# Generated by innovus_enablement/scripts/gen_fakeram.py: abstract 256x32 SRAM.
# Geometry is an assumption (see script header), not PDK data.
VERSION 5.8 ;
BUSBITCHARS "[]" ;
DIVIDERCHAR "/" ;

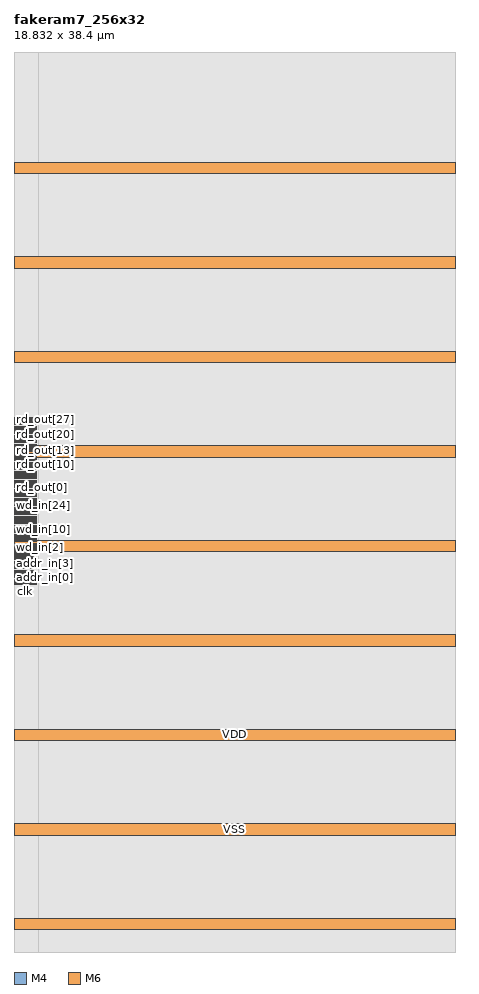
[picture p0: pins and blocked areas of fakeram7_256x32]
MACRO fakeram7_256x32
  CLASS BLOCK ;
  FOREIGN fakeram7_256x32 0 0 ;
  ORIGIN 0 0 ;
  SIZE 18.8320 BY 38.4000 ;
  SYMMETRY X Y R90 ;
  PIN clk
    DIRECTION INPUT ;
    USE CLOCK ;
    PORT
      LAYER M4 ;
        RECT 0 15.6720 0.9600 15.7200 ;
    END
  END clk
  PIN ce_in
    DIRECTION INPUT ;
    USE SIGNAL ;
    PORT
      LAYER M4 ;
        RECT 0 15.7680 0.9600 15.8160 ;
    END
  END ce_in
  PIN we_in
    DIRECTION INPUT ;
    USE SIGNAL ;
    PORT
      LAYER M4 ;
        RECT 0 15.8640 0.9600 15.9120 ;
    END
  END we_in
  PIN addr_in[0]
    DIRECTION INPUT ;
    USE SIGNAL ;
    PORT
      LAYER M4 ;
        RECT 0 15.9600 0.9600 16.0080 ;
    END
  END addr_in[0]
  PIN addr_in[1]
    DIRECTION INPUT ;
    USE SIGNAL ;
    PORT
      LAYER M4 ;
        RECT 0 16.0560 0.9600 16.1040 ;
    END
  END addr_in[1]
  PIN addr_in[2]
    DIRECTION INPUT ;
    USE SIGNAL ;
    PORT
      LAYER M4 ;
        RECT 0 16.1520 0.9600 16.2000 ;
    END
  END addr_in[2]
  PIN addr_in[3]
    DIRECTION INPUT ;
    USE SIGNAL ;
    PORT
      LAYER M4 ;
        RECT 0 16.2480 0.9600 16.2960 ;
    END
  END addr_in[3]
  PIN addr_in[4]
    DIRECTION INPUT ;
    USE SIGNAL ;
    PORT
      LAYER M4 ;
        RECT 0 16.3440 0.9600 16.3920 ;
    END
  END addr_in[4]
  PIN addr_in[5]
    DIRECTION INPUT ;
    USE SIGNAL ;
    PORT
      LAYER M4 ;
        RECT 0 16.4400 0.9600 16.4880 ;
    END
  END addr_in[5]
  PIN addr_in[6]
    DIRECTION INPUT ;
    USE SIGNAL ;
    PORT
      LAYER M4 ;
        RECT 0 16.5360 0.9600 16.5840 ;
    END
  END addr_in[6]
  PIN addr_in[7]
    DIRECTION INPUT ;
    USE SIGNAL ;
    PORT
      LAYER M4 ;
        RECT 0 16.6320 0.9600 16.6800 ;
    END
  END addr_in[7]
  PIN wd_in[0]
    DIRECTION INPUT ;
    USE SIGNAL ;
    PORT
      LAYER M4 ;
        RECT 0 16.7280 0.9600 16.7760 ;
    END
  END wd_in[0]
  PIN wd_in[1]
    DIRECTION INPUT ;
    USE SIGNAL ;
    PORT
      LAYER M4 ;
        RECT 0 16.8240 0.9600 16.8720 ;
    END
  END wd_in[1]
  PIN wd_in[2]
    DIRECTION INPUT ;
    USE SIGNAL ;
    PORT
      LAYER M4 ;
        RECT 0 16.9200 0.9600 16.9680 ;
    END
  END wd_in[2]
  PIN wd_in[3]
    DIRECTION INPUT ;
    USE SIGNAL ;
    PORT
      LAYER M4 ;
        RECT 0 17.0160 0.9600 17.0640 ;
    END
  END wd_in[3]
  PIN wd_in[4]
    DIRECTION INPUT ;
    USE SIGNAL ;
    PORT
      LAYER M4 ;
        RECT 0 17.1120 0.9600 17.1600 ;
    END
  END wd_in[4]
  PIN wd_in[5]
    DIRECTION INPUT ;
    USE SIGNAL ;
    PORT
      LAYER M4 ;
        RECT 0 17.2080 0.9600 17.2560 ;
    END
  END wd_in[5]
  PIN wd_in[6]
    DIRECTION INPUT ;
    USE SIGNAL ;
    PORT
      LAYER M4 ;
        RECT 0 17.3040 0.9600 17.3520 ;
    END
  END wd_in[6]
  PIN wd_in[7]
    DIRECTION INPUT ;
    USE SIGNAL ;
    PORT
      LAYER M4 ;
        RECT 0 17.4000 0.9600 17.4480 ;
    END
  END wd_in[7]
  PIN wd_in[8]
    DIRECTION INPUT ;
    USE SIGNAL ;
    PORT
      LAYER M4 ;
        RECT 0 17.4960 0.9600 17.5440 ;
    END
  END wd_in[8]
  PIN wd_in[9]
    DIRECTION INPUT ;
    USE SIGNAL ;
    PORT
      LAYER M4 ;
        RECT 0 17.5920 0.9600 17.6400 ;
    END
  END wd_in[9]
  PIN wd_in[10]
    DIRECTION INPUT ;
    USE SIGNAL ;
    PORT
      LAYER M4 ;
        RECT 0 17.6880 0.9600 17.7360 ;
    END
  END wd_in[10]
  PIN wd_in[11]
    DIRECTION INPUT ;
    USE SIGNAL ;
    PORT
      LAYER M4 ;
        RECT 0 17.7840 0.9600 17.8320 ;
    END
  END wd_in[11]
  PIN wd_in[12]
    DIRECTION INPUT ;
    USE SIGNAL ;
    PORT
      LAYER M4 ;
        RECT 0 17.8800 0.9600 17.9280 ;
    END
  END wd_in[12]
  PIN wd_in[13]
    DIRECTION INPUT ;
    USE SIGNAL ;
    PORT
      LAYER M4 ;
        RECT 0 17.9760 0.9600 18.0240 ;
    END
  END wd_in[13]
  PIN wd_in[14]
    DIRECTION INPUT ;
    USE SIGNAL ;
    PORT
      LAYER M4 ;
        RECT 0 18.0720 0.9600 18.1200 ;
    END
  END wd_in[14]
  PIN wd_in[15]
    DIRECTION INPUT ;
    USE SIGNAL ;
    PORT
      LAYER M4 ;
        RECT 0 18.1680 0.9600 18.2160 ;
    END
  END wd_in[15]
  PIN wd_in[16]
    DIRECTION INPUT ;
    USE SIGNAL ;
    PORT
      LAYER M4 ;
        RECT 0 18.2640 0.9600 18.3120 ;
    END
  END wd_in[16]
  PIN wd_in[17]
    DIRECTION INPUT ;
    USE SIGNAL ;
    PORT
      LAYER M4 ;
        RECT 0 18.3600 0.9600 18.4080 ;
    END
  END wd_in[17]
  PIN wd_in[18]
    DIRECTION INPUT ;
    USE SIGNAL ;
    PORT
      LAYER M4 ;
        RECT 0 18.4560 0.9600 18.5040 ;
    END
  END wd_in[18]
  PIN wd_in[19]
    DIRECTION INPUT ;
    USE SIGNAL ;
    PORT
      LAYER M4 ;
        RECT 0 18.5520 0.9600 18.6000 ;
    END
  END wd_in[19]
  PIN wd_in[20]
    DIRECTION INPUT ;
    USE SIGNAL ;
    PORT
      LAYER M4 ;
        RECT 0 18.6480 0.9600 18.6960 ;
    END
  END wd_in[20]
  PIN wd_in[21]
    DIRECTION INPUT ;
    USE SIGNAL ;
    PORT
      LAYER M4 ;
        RECT 0 18.7440 0.9600 18.7920 ;
    END
  END wd_in[21]
  PIN wd_in[22]
    DIRECTION INPUT ;
    USE SIGNAL ;
    PORT
      LAYER M4 ;
        RECT 0 18.8400 0.9600 18.8880 ;
    END
  END wd_in[22]
  PIN wd_in[23]
    DIRECTION INPUT ;
    USE SIGNAL ;
    PORT
      LAYER M4 ;
        RECT 0 18.9360 0.9600 18.9840 ;
    END
  END wd_in[23]
  PIN wd_in[24]
    DIRECTION INPUT ;
    USE SIGNAL ;
    PORT
      LAYER M4 ;
        RECT 0 19.0320 0.9600 19.0800 ;
    END
  END wd_in[24]
  PIN wd_in[25]
    DIRECTION INPUT ;
    USE SIGNAL ;
    PORT
      LAYER M4 ;
        RECT 0 19.1280 0.9600 19.1760 ;
    END
  END wd_in[25]
  PIN wd_in[26]
    DIRECTION INPUT ;
    USE SIGNAL ;
    PORT
      LAYER M4 ;
        RECT 0 19.2240 0.9600 19.2720 ;
    END
  END wd_in[26]
  PIN wd_in[27]
    DIRECTION INPUT ;
    USE SIGNAL ;
    PORT
      LAYER M4 ;
        RECT 0 19.3200 0.9600 19.3680 ;
    END
  END wd_in[27]
  PIN wd_in[28]
    DIRECTION INPUT ;
    USE SIGNAL ;
    PORT
      LAYER M4 ;
        RECT 0 19.4160 0.9600 19.4640 ;
    END
  END wd_in[28]
  PIN wd_in[29]
    DIRECTION INPUT ;
    USE SIGNAL ;
    PORT
      LAYER M4 ;
        RECT 0 19.5120 0.9600 19.5600 ;
    END
  END wd_in[29]
  PIN wd_in[30]
    DIRECTION INPUT ;
    USE SIGNAL ;
    PORT
      LAYER M4 ;
        RECT 0 19.6080 0.9600 19.6560 ;
    END
  END wd_in[30]
  PIN wd_in[31]
    DIRECTION INPUT ;
    USE SIGNAL ;
    PORT
      LAYER M4 ;
        RECT 0 19.7040 0.9600 19.7520 ;
    END
  END wd_in[31]
  PIN rd_out[0]
    DIRECTION OUTPUT ;
    USE SIGNAL ;
    PORT
      LAYER M4 ;
        RECT 0 19.8000 0.9600 19.8480 ;
    END
  END rd_out[0]
  PIN rd_out[1]
    DIRECTION OUTPUT ;
    USE SIGNAL ;
    PORT
      LAYER M4 ;
        RECT 0 19.8960 0.9600 19.9440 ;
    END
  END rd_out[1]
  PIN rd_out[2]
    DIRECTION OUTPUT ;
    USE SIGNAL ;
    PORT
      LAYER M4 ;
        RECT 0 19.9920 0.9600 20.0400 ;
    END
  END rd_out[2]
  PIN rd_out[3]
    DIRECTION OUTPUT ;
    USE SIGNAL ;
    PORT
      LAYER M4 ;
        RECT 0 20.0880 0.9600 20.1360 ;
    END
  END rd_out[3]
  PIN rd_out[4]
    DIRECTION OUTPUT ;
    USE SIGNAL ;
    PORT
      LAYER M4 ;
        RECT 0 20.1840 0.9600 20.2320 ;
    END
  END rd_out[4]
  PIN rd_out[5]
    DIRECTION OUTPUT ;
    USE SIGNAL ;
    PORT
      LAYER M4 ;
        RECT 0 20.2800 0.9600 20.3280 ;
    END
  END rd_out[5]
  PIN rd_out[6]
    DIRECTION OUTPUT ;
    USE SIGNAL ;
    PORT
      LAYER M4 ;
        RECT 0 20.3760 0.9600 20.4240 ;
    END
  END rd_out[6]
  PIN rd_out[7]
    DIRECTION OUTPUT ;
    USE SIGNAL ;
    PORT
      LAYER M4 ;
        RECT 0 20.4720 0.9600 20.5200 ;
    END
  END rd_out[7]
  PIN rd_out[8]
    DIRECTION OUTPUT ;
    USE SIGNAL ;
    PORT
      LAYER M4 ;
        RECT 0 20.5680 0.9600 20.6160 ;
    END
  END rd_out[8]
  PIN rd_out[9]
    DIRECTION OUTPUT ;
    USE SIGNAL ;
    PORT
      LAYER M4 ;
        RECT 0 20.6640 0.9600 20.7120 ;
    END
  END rd_out[9]
  PIN rd_out[10]
    DIRECTION OUTPUT ;
    USE SIGNAL ;
    PORT
      LAYER M4 ;
        RECT 0 20.7600 0.9600 20.8080 ;
    END
  END rd_out[10]
  PIN rd_out[11]
    DIRECTION OUTPUT ;
    USE SIGNAL ;
    PORT
      LAYER M4 ;
        RECT 0 20.8560 0.9600 20.9040 ;
    END
  END rd_out[11]
  PIN rd_out[12]
    DIRECTION OUTPUT ;
    USE SIGNAL ;
    PORT
      LAYER M4 ;
        RECT 0 20.9520 0.9600 21.0000 ;
    END
  END rd_out[12]
  PIN rd_out[13]
    DIRECTION OUTPUT ;
    USE SIGNAL ;
    PORT
      LAYER M4 ;
        RECT 0 21.0480 0.9600 21.0960 ;
    END
  END rd_out[13]
  PIN rd_out[14]
    DIRECTION OUTPUT ;
    USE SIGNAL ;
    PORT
      LAYER M4 ;
        RECT 0 21.1440 0.9600 21.1920 ;
    END
  END rd_out[14]
  PIN rd_out[15]
    DIRECTION OUTPUT ;
    USE SIGNAL ;
    PORT
      LAYER M4 ;
        RECT 0 21.2400 0.9600 21.2880 ;
    END
  END rd_out[15]
  PIN rd_out[16]
    DIRECTION OUTPUT ;
    USE SIGNAL ;
    PORT
      LAYER M4 ;
        RECT 0 21.3360 0.9600 21.3840 ;
    END
  END rd_out[16]
  PIN rd_out[17]
    DIRECTION OUTPUT ;
    USE SIGNAL ;
    PORT
      LAYER M4 ;
        RECT 0 21.4320 0.9600 21.4800 ;
    END
  END rd_out[17]
  PIN rd_out[18]
    DIRECTION OUTPUT ;
    USE SIGNAL ;
    PORT
      LAYER M4 ;
        RECT 0 21.5280 0.9600 21.5760 ;
    END
  END rd_out[18]
  PIN rd_out[19]
    DIRECTION OUTPUT ;
    USE SIGNAL ;
    PORT
      LAYER M4 ;
        RECT 0 21.6240 0.9600 21.6720 ;
    END
  END rd_out[19]
  PIN rd_out[20]
    DIRECTION OUTPUT ;
    USE SIGNAL ;
    PORT
      LAYER M4 ;
        RECT 0 21.7200 0.9600 21.7680 ;
    END
  END rd_out[20]
  PIN rd_out[21]
    DIRECTION OUTPUT ;
    USE SIGNAL ;
    PORT
      LAYER M4 ;
        RECT 0 21.8160 0.9600 21.8640 ;
    END
  END rd_out[21]
  PIN rd_out[22]
    DIRECTION OUTPUT ;
    USE SIGNAL ;
    PORT
      LAYER M4 ;
        RECT 0 21.9120 0.9600 21.9600 ;
    END
  END rd_out[22]
  PIN rd_out[23]
    DIRECTION OUTPUT ;
    USE SIGNAL ;
    PORT
      LAYER M4 ;
        RECT 0 22.0080 0.9600 22.0560 ;
    END
  END rd_out[23]
  PIN rd_out[24]
    DIRECTION OUTPUT ;
    USE SIGNAL ;
    PORT
      LAYER M4 ;
        RECT 0 22.1040 0.9600 22.1520 ;
    END
  END rd_out[24]
  PIN rd_out[25]
    DIRECTION OUTPUT ;
    USE SIGNAL ;
    PORT
      LAYER M4 ;
        RECT 0 22.2000 0.9600 22.2480 ;
    END
  END rd_out[25]
  PIN rd_out[26]
    DIRECTION OUTPUT ;
    USE SIGNAL ;
    PORT
      LAYER M4 ;
        RECT 0 22.2960 0.9600 22.3440 ;
    END
  END rd_out[26]
  PIN rd_out[27]
    DIRECTION OUTPUT ;
    USE SIGNAL ;
    PORT
      LAYER M4 ;
        RECT 0 22.3920 0.9600 22.4400 ;
    END
  END rd_out[27]
  PIN rd_out[28]
    DIRECTION OUTPUT ;
    USE SIGNAL ;
    PORT
      LAYER M4 ;
        RECT 0 22.4880 0.9600 22.5360 ;
    END
  END rd_out[28]
  PIN rd_out[29]
    DIRECTION OUTPUT ;
    USE SIGNAL ;
    PORT
      LAYER M4 ;
        RECT 0 22.5840 0.9600 22.6320 ;
    END
  END rd_out[29]
  PIN rd_out[30]
    DIRECTION OUTPUT ;
    USE SIGNAL ;
    PORT
      LAYER M4 ;
        RECT 0 22.6800 0.9600 22.7280 ;
    END
  END rd_out[30]
  PIN rd_out[31]
    DIRECTION OUTPUT ;
    USE SIGNAL ;
    PORT
      LAYER M4 ;
        RECT 0 22.7760 0.9600 22.8240 ;
    END
  END rd_out[31]
  PIN VDD
    DIRECTION INOUT ;
    USE POWER ;
    PORT
      LAYER M6 ;
        RECT 0 0.9600 18.8320 1.4400 ;
        RECT 0 9.0240 18.8320 9.5040 ;
        RECT 0 17.0880 18.8320 17.5680 ;
        RECT 0 25.1520 18.8320 25.6320 ;
        RECT 0 33.2160 18.8320 33.6960 ;
    END
  END VDD
  PIN VSS
    DIRECTION INOUT ;
    USE GROUND ;
    PORT
      LAYER M6 ;
        RECT 0 4.9920 18.8320 5.4720 ;
        RECT 0 13.0560 18.8320 13.5360 ;
        RECT 0 21.1200 18.8320 21.6000 ;
        RECT 0 29.1840 18.8320 29.6640 ;
    END
  END VSS
  OBS
    LAYER M0 ;
      RECT 0 0 18.8320 38.4000 ;
    LAYER M1 ;
      RECT 0 0 18.8320 38.4000 ;
    LAYER M2 ;
      RECT 0 0 18.8320 38.4000 ;
    LAYER M3 ;
      RECT 0 0 18.8320 38.4000 ;
    LAYER VIA0 ;
      RECT 0 0 18.8320 38.4000 ;
    LAYER VIA1 ;
      RECT 0 0 18.8320 38.4000 ;
    LAYER VIA2 ;
      RECT 0 0 18.8320 38.4000 ;
    LAYER VIA3 ;
      RECT 0 0 18.8320 38.4000 ;
    LAYER M4 ;
      RECT 1.0560 0 18.8320 38.4000 ;
  END
END fakeram7_256x32

END LIBRARY
